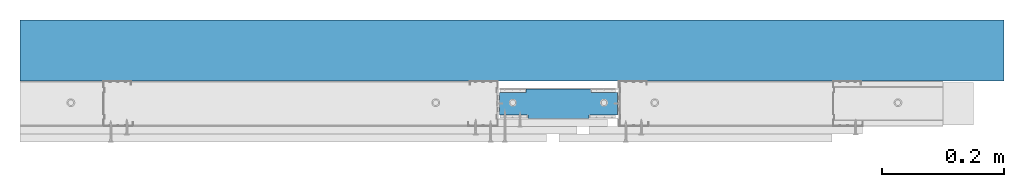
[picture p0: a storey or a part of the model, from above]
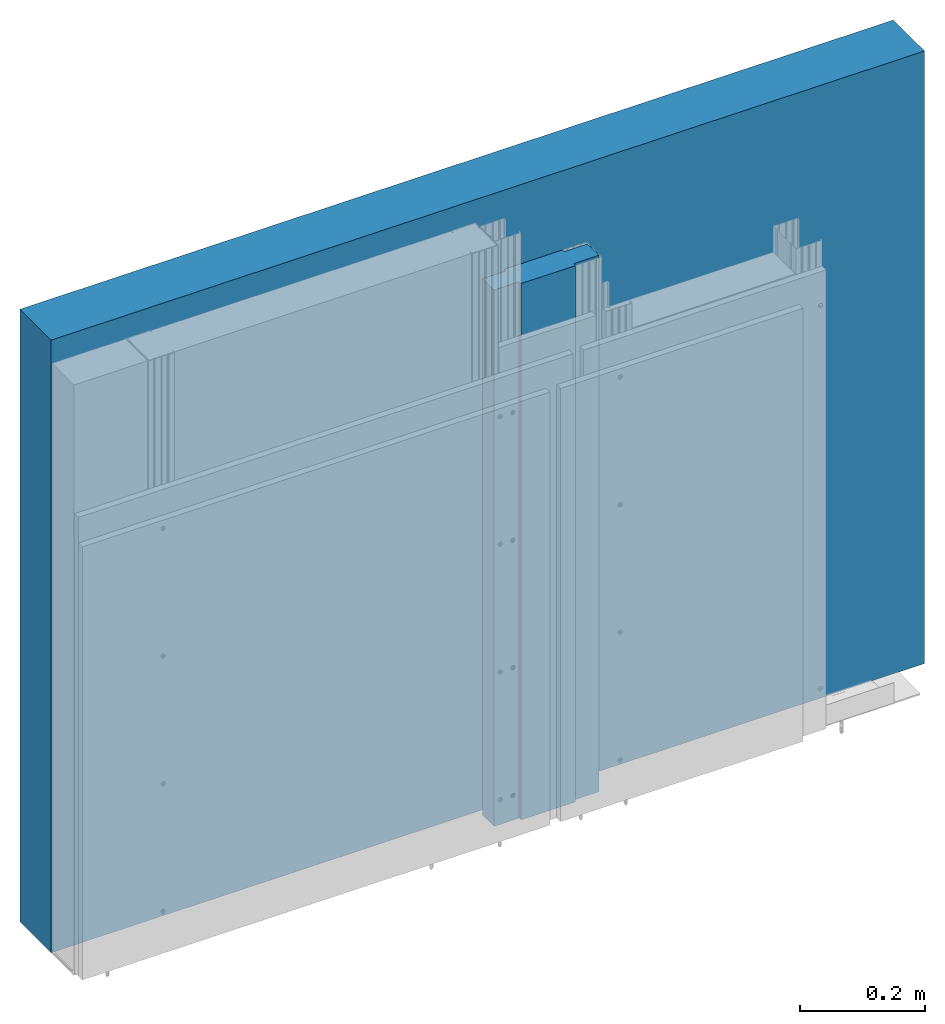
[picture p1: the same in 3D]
Properties of the parts of a building model (IFC2X3)

# File
Description: ViewDefinition [CoordinationView]
Time: 2022-01-07T10:15:48
Made in: SketchUp Pro 2015

# IfcProject, Default Project
Description: Description of Default Project

# IfcSite, Default Site
Description: Description of Default Site; RefLatitude: 24, 28, 0; RefLongitude: 54, 25, 0; RefElevation: 10 mm

# IfcBuilding, Default Building
Description: Description of Default Building

# IfcBuildingStorey, Default Building Storey
In: Default Building
Description: Description of Default Building Storey; Elevation: 0 mm

# IfcWall (71)
In: Default Building Storey
Description: Description of Object
Name
ŚCIANA
12 x Wkręt RIGIPS TN 35
12 x Wkręt RIGIPS TN 25
4 x Wełna mineralna szklana lub skalna ISOVER
12 x Kołek rozporowy min. fi 6
2 x Profil RIGIPS CW50 ULTRASTIL®
2 x Profil RIGIPS UW 75 ULTRASTIL®
3 x Taśma uszczelniająca piankowa RIGIPS
4 x Profil RIGIPS CW75 ULTRASTIL® | TempShadowInfo - City: Boulder (CO); Country: USA; Latitude: 40.017; Longitude: 40.017-105.283; NorthAngle: 40.017-105.2830; TZOffset: 40.017-105.2830-7
9 x Wkręt RIGIPS "pchełka" 3,9 x 11 mm
5 x Płyta gipsowo-kartonowa RIGIPS PRO (4PRO™)
4 x Wkręt RIGIPS TN 55
Profil RIGIPS UW 50 ULTRASTIL®
